VERSION 5.8 ;
BUSBITCHARS "[]" ;
DIVIDERCHAR "/" ;
UNITS
    DATABASE MICRONS 1000 ;
END UNITS

VIA PLL_ANALOG_MACRO_via2_3_960_480_1_3_320_320
  VIARULE M1M2_PR ;
  CUTSIZE 0.15 0.15 ;
  LAYERS met1 via met2 ;
  CUTSPACING 0.17 0.17 ;
  ENCLOSURE 0.085 0.165 0.055 0.085 ;
  ROWCOL 1 3 ;
END PLL_ANALOG_MACRO_via2_3_960_480_1_3_320_320

VIA PLL_ANALOG_MACRO_via3_4_960_480_1_2_400_400
  VIARULE M2M3_PR ;
  CUTSIZE 0.2 0.2 ;
  LAYERS met2 via2 met3 ;
  CUTSPACING 0.2 0.2 ;
  ENCLOSURE 0.04 0.085 0.065 0.065 ;
  ROWCOL 1 2 ;
END PLL_ANALOG_MACRO_via3_4_960_480_1_2_400_400

VIA PLL_ANALOG_MACRO_via4_5_960_480_1_2_400_400
  VIARULE M3M4_PR ;
  CUTSIZE 0.2 0.2 ;
  LAYERS met3 via3 met4 ;
  CUTSPACING 0.2 0.2 ;
  ENCLOSURE 0.09 0.06 0.18 0.065 ;
  ROWCOL 1 2 ;
END PLL_ANALOG_MACRO_via4_5_960_480_1_2_400_400

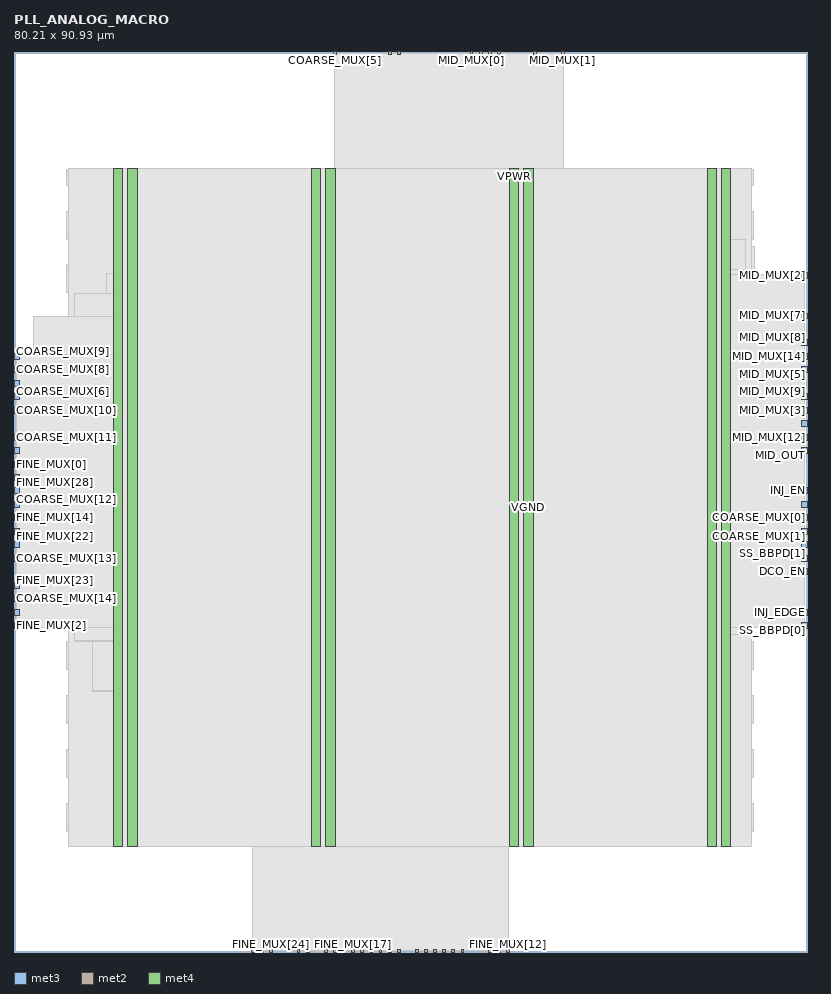
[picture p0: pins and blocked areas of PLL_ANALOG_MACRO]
MACRO PLL_ANALOG_MACRO
  FOREIGN PLL_ANALOG_MACRO 0 0 ;
  CLASS BLOCK ;
  SIZE 80.21 BY 90.93 ;
  PIN COARSE_MUX[0]
    DIRECTION INPUT ;
    USE SIGNAL ;
    PORT
      LAYER met3 ;
        RECT  79.61 43.56 80.21 44.16 ;
    END
  END COARSE_MUX[0]
  PIN COARSE_MUX[10]
    DIRECTION INPUT ;
    USE SIGNAL ;
    PORT
      LAYER met3 ;
        RECT  0 54.44 0.6 55.04 ;
    END
  END COARSE_MUX[10]
  PIN COARSE_MUX[11]
    DIRECTION INPUT ;
    USE SIGNAL ;
    PORT
      LAYER met3 ;
        RECT  0 51.72 0.6 52.32 ;
    END
  END COARSE_MUX[11]
  PIN COARSE_MUX[12]
    DIRECTION INPUT ;
    USE SIGNAL ;
    PORT
      LAYER met3 ;
        RECT  0 44.92 0.6 45.52 ;
    END
  END COARSE_MUX[12]
  PIN COARSE_MUX[13]
    DIRECTION INPUT ;
    USE SIGNAL ;
    PORT
      LAYER met3 ;
        RECT  0 39.48 0.6 40.08 ;
    END
  END COARSE_MUX[13]
  PIN COARSE_MUX[14]
    DIRECTION INPUT ;
    USE SIGNAL ;
    PORT
      LAYER met3 ;
        RECT  0 35.4 0.6 36 ;
    END
  END COARSE_MUX[14]
  PIN COARSE_MUX[1]
    DIRECTION INPUT ;
    USE SIGNAL ;
    PORT
      LAYER met3 ;
        RECT  79.61 42.2 80.21 42.8 ;
    END
  END COARSE_MUX[1]
  PIN COARSE_MUX[2]
    DIRECTION INPUT ;
    USE SIGNAL ;
    PORT
      LAYER met3 ;
        RECT  0 46.28 0.6 46.88 ;
    END
  END COARSE_MUX[2]
  PIN COARSE_MUX[3]
    DIRECTION INPUT ;
    USE SIGNAL ;
    PORT
      LAYER met2 ;
        RECT  37.81 90.65 38.09 90.93 ;
    END
  END COARSE_MUX[3]
  PIN COARSE_MUX[4]
    DIRECTION INPUT ;
    USE SIGNAL ;
    PORT
      LAYER met2 ;
        RECT  38.73 90.65 39.01 90.93 ;
    END
  END COARSE_MUX[4]
  PIN COARSE_MUX[5]
    DIRECTION INPUT ;
    USE SIGNAL ;
    PORT
      LAYER met2 ;
        RECT  32.29 90.65 32.57 90.93 ;
    END
  END COARSE_MUX[5]
  PIN COARSE_MUX[6]
    DIRECTION INPUT ;
    USE SIGNAL ;
    PORT
      LAYER met3 ;
        RECT  0 55.8 0.6 56.4 ;
    END
  END COARSE_MUX[6]
  PIN COARSE_MUX[7]
    DIRECTION INPUT ;
    USE SIGNAL ;
    PORT
      LAYER met3 ;
        RECT  0 57.16 0.6 57.76 ;
    END
  END COARSE_MUX[7]
  PIN COARSE_MUX[8]
    DIRECTION INPUT ;
    USE SIGNAL ;
    PORT
      LAYER met3 ;
        RECT  0 58.52 0.6 59.12 ;
    END
  END COARSE_MUX[8]
  PIN COARSE_MUX[9]
    DIRECTION INPUT ;
    USE SIGNAL ;
    PORT
      LAYER met3 ;
        RECT  0 59.88 0.6 60.48 ;
    END
  END COARSE_MUX[9]
  PIN DCO_EN
    DIRECTION INPUT ;
    USE SIGNAL ;
    PORT
      LAYER met3 ;
        RECT  79.61 38.12 80.21 38.72 ;
    END
  END DCO_EN
  PIN FINE_MUX[0]
    DIRECTION INPUT ;
    USE SIGNAL ;
    PORT
      LAYER met3 ;
        RECT  0 49 0.6 49.6 ;
    END
  END FINE_MUX[0]
  PIN FINE_MUX[10]
    DIRECTION INPUT ;
    USE SIGNAL ;
    PORT
      LAYER met2 ;
        RECT  43.33 0 43.61 0.28 ;
    END
  END FINE_MUX[10]
  PIN FINE_MUX[11]
    DIRECTION INPUT ;
    USE SIGNAL ;
    PORT
      LAYER met2 ;
        RECT  41.49 0 41.77 0.28 ;
    END
  END FINE_MUX[11]
  PIN FINE_MUX[12]
    DIRECTION INPUT ;
    USE SIGNAL ;
    PORT
      LAYER met2 ;
        RECT  49.77 0 50.05 0.28 ;
    END
  END FINE_MUX[12]
  PIN FINE_MUX[13]
    DIRECTION INPUT ;
    USE SIGNAL ;
    PORT
      LAYER met2 ;
        RECT  37.81 0 38.09 0.28 ;
    END
  END FINE_MUX[13]
  PIN FINE_MUX[14]
    DIRECTION INPUT ;
    USE SIGNAL ;
    PORT
      LAYER met3 ;
        RECT  0 43.56 0.6 44.16 ;
    END
  END FINE_MUX[14]
  PIN FINE_MUX[15]
    DIRECTION INPUT ;
    USE SIGNAL ;
    PORT
      LAYER met2 ;
        RECT  40.57 0 40.85 0.28 ;
    END
  END FINE_MUX[15]
  PIN FINE_MUX[16]
    DIRECTION INPUT ;
    USE SIGNAL ;
    PORT
      LAYER met2 ;
        RECT  35.05 0 35.33 0.28 ;
    END
  END FINE_MUX[16]
  PIN FINE_MUX[17]
    DIRECTION INPUT ;
    USE SIGNAL ;
    PORT
      LAYER met2 ;
        RECT  34.13 0 34.41 0.28 ;
    END
  END FINE_MUX[17]
  PIN FINE_MUX[18]
    DIRECTION INPUT ;
    USE SIGNAL ;
    PORT
      LAYER met2 ;
        RECT  32.29 0 32.57 0.28 ;
    END
  END FINE_MUX[18]
  PIN FINE_MUX[19]
    DIRECTION INPUT ;
    USE SIGNAL ;
    PORT
      LAYER met2 ;
        RECT  29.53 0 29.81 0.28 ;
    END
  END FINE_MUX[19]
  PIN FINE_MUX[1]
    DIRECTION INPUT ;
    USE SIGNAL ;
    PORT
      LAYER met2 ;
        RECT  48.85 0 49.13 0.28 ;
    END
  END FINE_MUX[1]
  PIN FINE_MUX[20]
    DIRECTION INPUT ;
    USE SIGNAL ;
    PORT
      LAYER met2 ;
        RECT  44.25 0 44.53 0.28 ;
    END
  END FINE_MUX[20]
  PIN FINE_MUX[21]
    DIRECTION INPUT ;
    USE SIGNAL ;
    PORT
      LAYER met2 ;
        RECT  42.41 0 42.69 0.28 ;
    END
  END FINE_MUX[21]
  PIN FINE_MUX[22]
    DIRECTION INPUT ;
    USE SIGNAL ;
    PORT
      LAYER met3 ;
        RECT  0 42.2 0.6 42.8 ;
    END
  END FINE_MUX[22]
  PIN FINE_MUX[23]
    DIRECTION INPUT ;
    USE SIGNAL ;
    PORT
      LAYER met3 ;
        RECT  0 36.76 0.6 37.36 ;
    END
  END FINE_MUX[23]
  PIN FINE_MUX[24]
    DIRECTION INPUT ;
    USE SIGNAL ;
    PORT
      LAYER met2 ;
        RECT  25.85 0 26.13 0.28 ;
    END
  END FINE_MUX[24]
  PIN FINE_MUX[25]
    DIRECTION INPUT ;
    USE SIGNAL ;
    PORT
      LAYER met2 ;
        RECT  24.93 0 25.21 0.28 ;
    END
  END FINE_MUX[25]
  PIN FINE_MUX[26]
    DIRECTION INPUT ;
    USE SIGNAL ;
    PORT
      LAYER met3 ;
        RECT  0 40.84 0.6 41.44 ;
    END
  END FINE_MUX[26]
  PIN FINE_MUX[27]
    DIRECTION INPUT ;
    USE SIGNAL ;
    PORT
      LAYER met2 ;
        RECT  31.37 0 31.65 0.28 ;
    END
  END FINE_MUX[27]
  PIN FINE_MUX[28]
    DIRECTION INPUT ;
    USE SIGNAL ;
    PORT
      LAYER met3 ;
        RECT  0 47.64 0.6 48.24 ;
    END
  END FINE_MUX[28]
  PIN FINE_MUX[29]
    DIRECTION INPUT ;
    USE SIGNAL ;
    PORT
      LAYER met2 ;
        RECT  47.93 0 48.21 0.28 ;
    END
  END FINE_MUX[29]
  PIN FINE_MUX[2]
    DIRECTION INPUT ;
    USE SIGNAL ;
    PORT
      LAYER met3 ;
        RECT  0 32.68 0.6 33.28 ;
    END
  END FINE_MUX[2]
  PIN FINE_MUX[30]
    DIRECTION INPUT ;
    USE SIGNAL ;
    PORT
      LAYER met2 ;
        RECT  35.97 0 36.25 0.28 ;
    END
  END FINE_MUX[30]
  PIN FINE_MUX[3]
    DIRECTION INPUT ;
    USE SIGNAL ;
    PORT
      LAYER met3 ;
        RECT  0 50.36 0.6 50.96 ;
    END
  END FINE_MUX[3]
  PIN FINE_MUX[4]
    DIRECTION INPUT ;
    USE SIGNAL ;
    PORT
      LAYER met2 ;
        RECT  36.89 0 37.17 0.28 ;
    END
  END FINE_MUX[4]
  PIN FINE_MUX[5]
    DIRECTION INPUT ;
    USE SIGNAL ;
    PORT
      LAYER met3 ;
        RECT  0 34.04 0.6 34.64 ;
    END
  END FINE_MUX[5]
  PIN FINE_MUX[6]
    DIRECTION INPUT ;
    USE SIGNAL ;
    PORT
      LAYER met2 ;
        RECT  45.17 0 45.45 0.28 ;
    END
  END FINE_MUX[6]
  PIN FINE_MUX[7]
    DIRECTION INPUT ;
    USE SIGNAL ;
    PORT
      LAYER met2 ;
        RECT  38.73 0 39.01 0.28 ;
    END
  END FINE_MUX[7]
  PIN FINE_MUX[8]
    DIRECTION INPUT ;
    USE SIGNAL ;
    PORT
      LAYER met2 ;
        RECT  24.01 0 24.29 0.28 ;
    END
  END FINE_MUX[8]
  PIN FINE_MUX[9]
    DIRECTION INPUT ;
    USE SIGNAL ;
    PORT
      LAYER met2 ;
        RECT  28.61 0 28.89 0.28 ;
    END
  END FINE_MUX[9]
  PIN INJ_EDGE
    DIRECTION OUTPUT ;
    USE SIGNAL ;
    PORT
      LAYER met3 ;
        RECT  79.61 34.04 80.21 34.64 ;
    END
  END INJ_EDGE
  PIN INJ_EN
    DIRECTION INPUT ;
    USE SIGNAL ;
    PORT
      LAYER met3 ;
        RECT  79.61 46.28 80.21 46.88 ;
    END
  END INJ_EN
  PIN MID_MUX[0]
    DIRECTION INPUT ;
    USE SIGNAL ;
    PORT
      LAYER met2 ;
        RECT  46.09 90.65 46.37 90.93 ;
    END
  END MID_MUX[0]
  PIN MID_MUX[10]
    DIRECTION INPUT ;
    USE SIGNAL ;
    PORT
      LAYER met2 ;
        RECT  47.01 90.65 47.29 90.93 ;
    END
  END MID_MUX[10]
  PIN MID_MUX[11]
    DIRECTION INPUT ;
    USE SIGNAL ;
    PORT
      LAYER met2 ;
        RECT  52.53 90.65 52.81 90.93 ;
    END
  END MID_MUX[11]
  PIN MID_MUX[12]
    DIRECTION INPUT ;
    USE SIGNAL ;
    PORT
      LAYER met3 ;
        RECT  79.61 51.72 80.21 52.32 ;
    END
  END MID_MUX[12]
  PIN MID_MUX[13]
    DIRECTION INPUT ;
    USE SIGNAL ;
    PORT
      LAYER met2 ;
        RECT  48.85 90.65 49.13 90.93 ;
    END
  END MID_MUX[13]
  PIN MID_MUX[14]
    DIRECTION INPUT ;
    USE SIGNAL ;
    PORT
      LAYER met3 ;
        RECT  79.61 59.88 80.21 60.48 ;
    END
  END MID_MUX[14]
  PIN MID_MUX[1]
    DIRECTION INPUT ;
    USE SIGNAL ;
    PORT
      LAYER met2 ;
        RECT  55.29 90.65 55.57 90.93 ;
    END
  END MID_MUX[1]
  PIN MID_MUX[2]
    DIRECTION INPUT ;
    USE SIGNAL ;
    PORT
      LAYER met3 ;
        RECT  79.61 68.04 80.21 68.64 ;
    END
  END MID_MUX[2]
  PIN MID_MUX[3]
    DIRECTION INPUT ;
    USE SIGNAL ;
    PORT
      LAYER met3 ;
        RECT  79.61 54.44 80.21 55.04 ;
    END
  END MID_MUX[3]
  PIN MID_MUX[4]
    DIRECTION INPUT ;
    USE SIGNAL ;
    PORT
      LAYER met2 ;
        RECT  47.93 90.65 48.21 90.93 ;
    END
  END MID_MUX[4]
  PIN MID_MUX[5]
    DIRECTION INPUT ;
    USE SIGNAL ;
    PORT
      LAYER met3 ;
        RECT  79.61 58.52 80.21 59.12 ;
    END
  END MID_MUX[5]
  PIN MID_MUX[6]
    DIRECTION INPUT ;
    USE SIGNAL ;
    PORT
      LAYER met3 ;
        RECT  79.61 53.08 80.21 53.68 ;
    END
  END MID_MUX[6]
  PIN MID_MUX[7]
    DIRECTION INPUT ;
    USE SIGNAL ;
    PORT
      LAYER met3 ;
        RECT  79.61 63.96 80.21 64.56 ;
    END
  END MID_MUX[7]
  PIN MID_MUX[8]
    DIRECTION INPUT ;
    USE SIGNAL ;
    PORT
      LAYER met3 ;
        RECT  79.61 61.24 80.21 61.84 ;
    END
  END MID_MUX[8]
  PIN MID_MUX[9]
    DIRECTION INPUT ;
    USE SIGNAL ;
    PORT
      LAYER met3 ;
        RECT  79.61 55.8 80.21 56.4 ;
    END
  END MID_MUX[9]
  PIN MID_OUT
    DIRECTION OUTPUT ;
    USE SIGNAL ;
    PORT
      LAYER met3 ;
        RECT  79.61 50.36 80.21 50.96 ;
    END
  END MID_OUT
  PIN OUT
    DIRECTION OUTPUT ;
    USE SIGNAL ;
    PORT
      LAYER met3 ;
        RECT  79.61 40.84 80.21 41.44 ;
    END
  END OUT
  PIN REF
    DIRECTION INPUT ;
    USE SIGNAL ;
    PORT
      LAYER met3 ;
        RECT  79.61 44.92 80.21 45.52 ;
    END
  END REF
  PIN SS_BBPD[0]
    DIRECTION OUTPUT ;
    USE SIGNAL ;
    PORT
      LAYER met3 ;
        RECT  79.61 32.68 80.21 33.28 ;
    END
  END SS_BBPD[0]
  PIN SS_BBPD[1]
    DIRECTION OUTPUT ;
    USE SIGNAL ;
    PORT
      LAYER met3 ;
        RECT  79.61 39.48 80.21 40.08 ;
    END
  END SS_BBPD[1]
  PIN VGND
    DIRECTION INOUT ;
    USE GROUND ;
    PORT
      LAYER met4 ;
        RECT  71.48 10.64 72.44 79.12 ;
        RECT  51.48 10.64 52.44 79.12 ;
        RECT  31.48 10.64 32.44 79.12 ;
        RECT  11.48 10.64 12.44 79.12 ;
    END
  END VGND
  PIN VPWR
    DIRECTION INOUT ;
    USE POWER ;
    PORT
      LAYER met4 ;
        RECT  70.04 10.64 71 79.12 ;
        RECT  50.04 10.64 51 79.12 ;
        RECT  30.04 10.64 31 79.12 ;
        RECT  10.04 10.64 11 79.12 ;
    END
  END VPWR
  OBS
    LAYER nwell ;
     RECT  5.33 12.19 74.71 15.01 ;
     RECT  5.33 17.63 74.71 20.45 ;
     RECT  5.33 23.07 74.71 25.89 ;
     RECT  5.33 28.51 74.71 31.33 ;
     RECT  5.33 33.95 74.71 36.77 ;
     RECT  5.33 39.39 74.71 42.21 ;
     RECT  5.33 44.83 74.71 47.65 ;
     RECT  5.33 50.27 74.71 53.09 ;
     RECT  5.33 55.71 74.71 58.53 ;
     RECT  5.33 61.15 74.71 63.97 ;
     RECT  5.33 66.59 74.71 69.41 ;
     RECT  5.33 72.03 74.71 74.85 ;
     RECT  5.33 77.47 74.71 79.07 ;
    LAYER pwell ;
     RECT  18.53 10.78 18.73 10.805 ;
     RECT  56.25 10.78 56.45 10.805 ;
     RECT  72.79 10.77 73.04 10.805 ;
     RECT  6.1 10.77 6.5 10.86 ;
     RECT  53.95 10.78 54.27 10.86 ;
     RECT  57.62 10.77 58.02 10.86 ;
     RECT  65.44 10.77 65.84 10.86 ;
     RECT  72.79 10.805 73.06 10.86 ;
     RECT  5.61 10.76 5.92 10.99 ;
     RECT  5.98 10.86 13.34 10.99 ;
     RECT  18.48 10.805 18.73 10.99 ;
     RECT  21.17 10.78 21.51 10.99 ;
     RECT  23.01 10.78 23.35 10.99 ;
     RECT  24.85 10.78 25.19 10.99 ;
     RECT  25.39 10.76 25.7 10.99 ;
     RECT  28.07 10.78 28.41 10.99 ;
     RECT  29.91 10.78 30.25 10.99 ;
     RECT  31.75 10.78 32.09 10.99 ;
     RECT  33.59 10.78 33.93 10.99 ;
     RECT  35.43 10.78 35.77 10.99 ;
     RECT  37.27 10.78 37.61 10.99 ;
     RECT  39.11 10.78 39.45 10.99 ;
     RECT  40.95 10.78 41.29 10.99 ;
     RECT  42.79 10.78 43.13 10.99 ;
     RECT  43.35 10.78 43.69 10.99 ;
     RECT  45.17 10.76 45.48 10.99 ;
     RECT  45.65 10.78 45.99 10.99 ;
     RECT  48.41 10.78 48.75 10.99 ;
     RECT  50.25 10.78 50.59 10.99 ;
     RECT  52.09 10.78 52.43 10.99 ;
     RECT  56.25 10.805 56.5 10.99 ;
     RECT  57.5 10.86 64.86 10.99 ;
     RECT  64.95 10.76 65.26 10.99 ;
     RECT  65.32 10.86 74.06 10.99 ;
     RECT  74.12 10.76 74.43 10.99 ;
     RECT  21.07 10.99 21.51 11.03 ;
     RECT  22.91 10.99 23.35 11.03 ;
     RECT  24.75 10.99 25.19 11.03 ;
     RECT  27.97 10.99 28.41 11.03 ;
     RECT  29.81 10.99 30.25 11.03 ;
     RECT  31.65 10.99 32.09 11.03 ;
     RECT  33.49 10.99 33.93 11.03 ;
     RECT  35.33 10.99 35.77 11.03 ;
     RECT  37.17 10.99 37.61 11.03 ;
     RECT  39.01 10.99 39.45 11.03 ;
     RECT  40.85 10.99 41.29 11.03 ;
     RECT  42.69 10.99 43.13 11.03 ;
     RECT  43.35 10.99 43.79 11.03 ;
     RECT  45.65 10.99 46.09 11.03 ;
     RECT  48.41 10.99 48.85 11.03 ;
     RECT  50.25 10.99 50.69 11.03 ;
     RECT  52.09 10.99 52.53 11.03 ;
     RECT  21.17 11.03 21.51 11.09 ;
     RECT  23.01 11.03 23.35 11.09 ;
     RECT  24.85 11.03 25.19 11.09 ;
     RECT  28.07 11.03 28.41 11.09 ;
     RECT  29.91 11.03 30.25 11.09 ;
     RECT  31.75 11.03 32.09 11.09 ;
     RECT  33.59 11.03 33.93 11.09 ;
     RECT  35.43 11.03 35.77 11.09 ;
     RECT  37.27 11.03 37.61 11.09 ;
     RECT  39.11 11.03 39.45 11.09 ;
     RECT  40.95 11.03 41.29 11.09 ;
     RECT  42.79 11.03 43.13 11.09 ;
     RECT  43.35 11.03 43.69 11.09 ;
     RECT  45.65 11.03 45.99 11.09 ;
     RECT  48.41 11.03 48.75 11.09 ;
     RECT  50.25 11.03 50.59 11.09 ;
     RECT  52.09 11.03 52.43 11.09 ;
     RECT  5.52 10.99 13.34 11.9 ;
     RECT  17.48 10.99 18.86 11.9 ;
     RECT  19.81 11.09 21.59 11.9 ;
     RECT  21.65 11.09 23.43 11.9 ;
     RECT  23.49 11.09 25.27 11.9 ;
     RECT  25.3 10.99 25.76 11.9 ;
     RECT  26.71 11.09 28.49 11.9 ;
     RECT  28.55 11.09 30.33 11.9 ;
     RECT  30.39 11.09 32.17 11.9 ;
     RECT  32.23 11.09 34.01 11.9 ;
     RECT  34.07 11.09 35.85 11.9 ;
     RECT  35.91 11.09 37.69 11.9 ;
     RECT  37.75 11.09 39.53 11.9 ;
     RECT  39.59 11.09 41.37 11.9 ;
     RECT  41.43 11.09 43.21 11.9 ;
     RECT  43.27 11.09 45.05 11.9 ;
     RECT  45.08 10.99 45.54 11.9 ;
     RECT  45.57 11.09 47.35 11.9 ;
     RECT  48.33 11.09 50.11 11.9 ;
     RECT  50.17 11.09 51.95 11.9 ;
     RECT  52.01 11.09 53.79 11.9 ;
     RECT  53.82 10.86 55.66 11.9 ;
     RECT  56.12 10.99 74.52 11.9 ;
     RECT  32.23 15.3 34.01 16.11 ;
     RECT  33.59 16.11 33.93 16.17 ;
     RECT  5.52 15.3 15.18 16.21 ;
     RECT  33.49 16.17 33.93 16.21 ;
     RECT  34.04 15.3 45.54 16.21 ;
     RECT  46.46 15.3 73.6 16.21 ;
     RECT  74.06 15.3 74.52 16.21 ;
     RECT  16.1 15.3 19.78 16.22 ;
     RECT  20.24 15.3 23.92 16.22 ;
     RECT  24.84 15.3 32.2 16.22 ;
     RECT  34.04 16.21 45.08 16.22 ;
     RECT  46.46 16.21 50.14 16.22 ;
     RECT  51.52 16.21 73.6 16.22 ;
     RECT  20.83 16.22 21.03 16.245 ;
     RECT  22.21 16.22 22.41 16.245 ;
     RECT  26.81 16.22 27.01 16.245 ;
     RECT  35.09 16.22 35.29 16.245 ;
     RECT  41.07 16.22 41.27 16.245 ;
     RECT  43.37 16.22 43.57 16.245 ;
     RECT  47.51 16.22 47.71 16.245 ;
     RECT  52.57 16.22 52.77 16.245 ;
     RECT  5.98 16.21 15.18 16.3 ;
     RECT  17.1 16.22 17.35 16.3 ;
     RECT  19.33 16.22 19.65 16.3 ;
     RECT  20.37 16.22 20.69 16.3 ;
     RECT  44.75 16.22 45.07 16.3 ;
     RECT  45.17 16.21 45.48 16.3 ;
     RECT  53.94 16.22 54.34 16.3 ;
     RECT  55.33 16.22 55.65 16.3 ;
     RECT  57.63 16.22 57.88 16.3 ;
     RECT  58.88 16.22 73.6 16.3 ;
     RECT  53.82 16.3 74.06 16.34 ;
     RECT  22.67 16.22 22.92 16.395 ;
     RECT  27.27 16.22 27.52 16.395 ;
     RECT  30.95 16.22 31.2 16.395 ;
     RECT  40.15 16.22 40.4 16.395 ;
     RECT  43.83 16.22 44.08 16.395 ;
     RECT  48.89 16.22 49.14 16.395 ;
     RECT  50.27 16.21 50.52 16.395 ;
     RECT  22.67 16.395 22.87 16.42 ;
     RECT  24.85 16.22 25.29 16.42 ;
     RECT  27.27 16.395 27.47 16.42 ;
     RECT  28.65 16.22 28.97 16.42 ;
     RECT  30.95 16.395 31.15 16.42 ;
     RECT  32.79 16.22 33.11 16.42 ;
     RECT  33.59 16.21 33.93 16.42 ;
     RECT  34.17 16.22 34.49 16.42 ;
     RECT  35.09 16.245 35.34 16.42 ;
     RECT  37.85 16.22 38.17 16.42 ;
     RECT  40.15 16.395 40.35 16.42 ;
     RECT  41.53 16.22 41.85 16.42 ;
     RECT  43.83 16.395 44.03 16.42 ;
     RECT  46.59 16.22 46.91 16.42 ;
     RECT  48.89 16.395 49.09 16.42 ;
     RECT  50.27 16.395 50.47 16.42 ;
     RECT  51.65 16.22 51.97 16.42 ;
     RECT  5.61 16.21 5.92 16.43 ;
     RECT  5.98 16.3 20.7 16.43 ;
     RECT  20.83 16.245 21.08 16.43 ;
     RECT  22.21 16.245 22.46 16.43 ;
     RECT  24.85 16.42 25.19 16.43 ;
     RECT  25.39 16.22 25.7 16.43 ;
     RECT  26.81 16.245 27.06 16.43 ;
     RECT  28.65 16.42 28.9 16.43 ;
     RECT  30.01 16.22 30.35 16.43 ;
     RECT  36.45 16.22 36.79 16.43 ;
     RECT  38.29 16.22 38.63 16.43 ;
     RECT  41.07 16.245 41.32 16.43 ;
     RECT  43.37 16.245 43.62 16.43 ;
     RECT  44.62 16.3 46.46 16.43 ;
     RECT  47.51 16.245 47.76 16.43 ;
     RECT  52.57 16.245 52.82 16.43 ;
     RECT  53.82 16.34 61.18 16.43 ;
     RECT  64.95 16.34 65.26 16.43 ;
     RECT  65.32 16.34 74.06 16.43 ;
     RECT  74.12 16.21 74.43 16.43 ;
     RECT  24.75 16.43 25.19 16.47 ;
     RECT  30.01 16.43 30.45 16.47 ;
     RECT  36.45 16.43 36.89 16.47 ;
     RECT  38.29 16.43 38.73 16.47 ;
     RECT  24.85 16.47 25.19 16.53 ;
     RECT  30.01 16.47 30.35 16.53 ;
     RECT  36.45 16.47 36.79 16.53 ;
     RECT  38.29 16.47 38.63 16.53 ;
     RECT  5.52 16.43 23.46 17.34 ;
     RECT  23.49 16.53 25.27 17.34 ;
     RECT  25.3 16.43 25.76 17.34 ;
     RECT  26.68 16.43 28.06 17.34 ;
     RECT  28.52 16.43 29.9 17.34 ;
     RECT  29.93 16.53 31.71 17.34 ;
     RECT  32.66 16.42 36.34 17.34 ;
     RECT  36.37 16.53 38.15 17.34 ;
     RECT  38.21 16.53 39.99 17.34 ;
     RECT  40.94 16.43 42.32 17.34 ;
     RECT  43.24 16.43 46.46 17.34 ;
     RECT  47.38 16.43 48.76 17.34 ;
     RECT  52.44 16.43 61.18 17.34 ;
     RECT  64.86 16.43 74.52 17.34 ;
     RECT  5.52 20.74 27.6 21.65 ;
     RECT  28.52 20.74 29.9 21.65 ;
     RECT  33.58 20.74 34.96 21.65 ;
     RECT  35.42 20.74 36.8 21.65 ;
     RECT  37.26 20.74 38.64 21.65 ;
     RECT  39.56 20.74 40.94 21.65 ;
     RECT  45.08 20.74 45.54 21.65 ;
     RECT  50.6 20.74 70.38 21.65 ;
     RECT  74.06 20.74 74.52 21.65 ;
     RECT  5.98 21.65 27.6 21.66 ;
     RECT  46.46 20.74 50.14 21.66 ;
     RECT  51.98 21.65 70.38 21.66 ;
     RECT  31.87 21.66 32.07 21.685 ;
     RECT  33.25 21.66 33.45 21.685 ;
     RECT  41.07 21.66 41.27 21.685 ;
     RECT  42.91 21.66 43.11 21.685 ;
     RECT  72.79 21.65 73.04 21.685 ;
     RECT  44.29 21.66 44.61 21.74 ;
     RECT  45.17 21.65 45.48 21.74 ;
     RECT  47.96 21.66 48.36 21.74 ;
     RECT  48.89 21.66 49.14 21.74 ;
     RECT  51.6 21.65 51.85 21.74 ;
     RECT  52.11 21.66 52.43 21.74 ;
     RECT  54.41 21.66 54.66 21.74 ;
     RECT  55.32 21.66 70.38 21.74 ;
     RECT  72.79 21.685 73.06 21.74 ;
     RECT  5.98 21.66 22.08 21.78 ;
     RECT  25.76 21.66 27.6 21.78 ;
     RECT  47.84 21.74 74.06 21.78 ;
     RECT  20.81 21.78 21.08 21.835 ;
     RECT  24.51 21.66 24.76 21.835 ;
     RECT  28.65 21.65 28.9 21.835 ;
     RECT  33.71 21.65 33.96 21.835 ;
     RECT  35.55 21.65 35.8 21.835 ;
     RECT  39.69 21.65 39.94 21.835 ;
     RECT  22.21 21.66 22.53 21.86 ;
     RECT  24.51 21.835 24.71 21.86 ;
     RECT  25.89 21.78 26.21 21.86 ;
     RECT  26.76 21.78 27.01 21.86 ;
     RECT  28.65 21.835 28.85 21.86 ;
     RECT  28.99 21.66 29.31 21.86 ;
     RECT  29.57 21.66 29.89 21.86 ;
     RECT  31.87 21.685 32.12 21.86 ;
     RECT  33.71 21.835 33.91 21.86 ;
     RECT  35.09 21.66 35.41 21.86 ;
     RECT  35.55 21.835 35.75 21.86 ;
     RECT  37.39 21.65 37.64 21.86 ;
     RECT  38.77 21.66 39.09 21.86 ;
     RECT  39.69 21.835 39.89 21.86 ;
     RECT  41.07 21.685 41.32 21.86 ;
     RECT  46.59 21.66 46.91 21.86 ;
     RECT  5.61 21.65 5.92 21.87 ;
     RECT  5.98 21.78 20.7 21.87 ;
     RECT  20.81 21.835 21.06 21.87 ;
     RECT  25.39 21.66 25.7 21.87 ;
     RECT  25.76 21.86 33.12 21.87 ;
     RECT  33.25 21.685 33.5 21.87 ;
     RECT  42.91 21.685 43.16 21.87 ;
     RECT  44.16 21.74 46 21.87 ;
     RECT  46.59 21.86 46.84 21.87 ;
     RECT  47.84 21.78 64.4 21.87 ;
     RECT  64.95 21.78 65.26 21.87 ;
     RECT  65.32 21.78 74.06 21.87 ;
     RECT  74.12 21.65 74.43 21.87 ;
     RECT  5.52 21.87 20.7 22.78 ;
     RECT  25.3 21.87 34.5 22.78 ;
     RECT  34.96 21.86 42.32 22.78 ;
     RECT  42.78 21.87 46 22.78 ;
     RECT  46.46 21.87 64.4 22.78 ;
     RECT  64.86 21.87 74.52 22.78 ;
     RECT  5.52 26.18 33.12 27.09 ;
     RECT  33.58 26.18 40.48 27.09 ;
     RECT  41.4 26.18 73.14 27.09 ;
     RECT  74.06 26.18 74.52 27.09 ;
     RECT  33.24 27.09 37.26 27.1 ;
     RECT  41.4 27.09 45.08 27.1 ;
     RECT  45.54 27.09 73.14 27.1 ;
     RECT  7.95 27.1 8.15 27.125 ;
     RECT  9.2 27.09 33.12 27.18 ;
     RECT  33.24 27.1 33.64 27.18 ;
     RECT  34.58 27.1 34.83 27.18 ;
     RECT  36.81 27.1 37.13 27.18 ;
     RECT  37.39 27.09 37.64 27.18 ;
     RECT  38.64 27.09 40.48 27.18 ;
     RECT  40.6 27.09 41 27.18 ;
     RECT  41.53 27.1 41.85 27.18 ;
     RECT  43.83 27.1 44.08 27.18 ;
     RECT  45.17 27.09 45.48 27.18 ;
     RECT  45.67 27.1 45.99 27.18 ;
     RECT  47.96 27.1 48.36 27.18 ;
     RECT  49.22 27.1 73.14 27.18 ;
     RECT  5.98 27.09 7.82 27.22 ;
     RECT  9.2 27.18 73.14 27.22 ;
     RECT  8.82 27.09 9.07 27.275 ;
     RECT  6.11 27.22 6.43 27.3 ;
     RECT  7.9 27.125 8.15 27.3 ;
     RECT  8.87 27.275 9.07 27.3 ;
     RECT  9.32 27.22 9.72 27.3 ;
     RECT  10.13 27.22 10.45 27.3 ;
     RECT  10.58 27.22 25.3 27.3 ;
     RECT  71.43 27.22 71.75 27.3 ;
     RECT  5.61 27.09 5.92 27.31 ;
     RECT  6.9 27.3 25.3 27.31 ;
     RECT  25.39 27.22 25.7 27.31 ;
     RECT  25.76 27.22 55.2 27.31 ;
     RECT  56.7 27.22 57.1 27.31 ;
     RECT  60.37 27.22 60.71 27.31 ;
     RECT  62.67 27.22 63.01 27.31 ;
     RECT  64.06 27.22 64.46 27.31 ;
     RECT  64.95 27.22 65.26 27.31 ;
     RECT  74.12 27.09 74.43 27.31 ;
     RECT  60.37 27.31 60.81 27.35 ;
     RECT  62.67 27.31 63.11 27.35 ;
     RECT  60.37 27.35 60.71 27.41 ;
     RECT  62.67 27.35 63.01 27.41 ;
     RECT  65.43 27.22 65.73 27.42 ;
     RECT  65.43 27.42 73.36 27.44 ;
     RECT  5.52 27.31 5.98 28.22 ;
     RECT  6.9 27.31 55.2 28.22 ;
     RECT  58.88 27.22 60.26 28.22 ;
     RECT  60.29 27.41 62.07 28.22 ;
     RECT  62.59 27.41 64.37 28.22 ;
     RECT  64.86 27.31 65.32 28.22 ;
     RECT  65.41 27.44 74.03 28.22 ;
     RECT  74.06 27.31 74.52 28.22 ;
     RECT  6.01 31.62 7.79 32.43 ;
     RECT  7.85 31.62 9.63 32.43 ;
     RECT  70.41 31.62 72.19 32.43 ;
     RECT  72.25 31.62 74.03 32.43 ;
     RECT  6.09 32.43 6.43 32.49 ;
     RECT  7.93 32.43 8.27 32.49 ;
     RECT  71.77 32.43 72.11 32.49 ;
     RECT  72.33 32.43 72.67 32.49 ;
     RECT  5.52 31.62 5.98 32.53 ;
     RECT  6.09 32.49 6.53 32.53 ;
     RECT  7.93 32.49 8.37 32.53 ;
     RECT  9.66 31.62 54.74 32.53 ;
     RECT  55.66 31.62 70.38 32.53 ;
     RECT  71.67 32.49 72.11 32.53 ;
     RECT  72.33 32.49 72.77 32.53 ;
     RECT  74.06 31.62 74.52 32.53 ;
     RECT  20.7 32.53 40.48 32.54 ;
     RECT  7.93 32.53 8.27 32.565 ;
     RECT  20.7 32.54 36.8 32.62 ;
     RECT  37.8 32.54 38.05 32.62 ;
     RECT  40.03 32.54 40.35 32.62 ;
     RECT  40.6 32.53 41 32.62 ;
     RECT  41.86 32.53 45.08 32.62 ;
     RECT  45.17 32.53 45.48 32.62 ;
     RECT  45.54 32.53 54.74 32.62 ;
     RECT  59.01 32.54 59.33 32.62 ;
     RECT  60.39 32.53 60.64 32.62 ;
     RECT  11.04 32.53 18.4 32.66 ;
     RECT  20.7 32.62 55.2 32.66 ;
     RECT  61.64 32.53 70.38 32.66 ;
     RECT  9.79 32.53 10.04 32.715 ;
     RECT  69.11 32.66 69.38 32.715 ;
     RECT  6.09 32.53 6.43 32.74 ;
     RECT  7.9 32.565 8.27 32.74 ;
     RECT  9.79 32.715 9.99 32.74 ;
     RECT  10.13 32.54 10.45 32.74 ;
     RECT  18.53 32.53 18.85 32.74 ;
     RECT  55.79 32.53 56.11 32.74 ;
     RECT  58.09 32.53 58.41 32.74 ;
     RECT  72.33 32.53 72.67 32.74 ;
     RECT  5.61 32.53 5.92 32.75 ;
     RECT  10.69 32.54 11.03 32.75 ;
     RECT  11.16 32.66 11.56 32.75 ;
     RECT  16.1 32.66 17.94 32.75 ;
     RECT  18.07 32.66 18.32 32.75 ;
     RECT  19.45 32.54 19.77 32.75 ;
     RECT  20.82 32.66 21.22 32.75 ;
     RECT  21.73 32.66 22.07 32.75 ;
     RECT  23.46 32.66 25.3 32.75 ;
     RECT  25.39 32.66 25.7 32.75 ;
     RECT  25.76 32.66 55.2 32.75 ;
     RECT  61.29 32.54 61.63 32.75 ;
     RECT  61.76 32.66 62.16 32.75 ;
     RECT  63.13 32.66 63.47 32.75 ;
     RECT  64.95 32.66 65.26 32.75 ;
     RECT  65.32 32.66 68.54 32.75 ;
     RECT  69.11 32.715 69.36 32.75 ;
     RECT  69.93 32.66 70.27 32.75 ;
     RECT  71.77 32.53 72.11 32.75 ;
     RECT  73.61 32.54 73.95 32.75 ;
     RECT  74.12 32.53 74.43 32.75 ;
     RECT  10.69 32.75 11.13 32.79 ;
     RECT  21.73 32.75 22.17 32.79 ;
     RECT  61.29 32.75 61.73 32.79 ;
     RECT  63.13 32.75 63.57 32.79 ;
     RECT  69.83 32.75 70.27 32.79 ;
     RECT  71.67 32.75 72.11 32.79 ;
     RECT  73.51 32.75 73.95 32.79 ;
     RECT  10.69 32.79 11.03 32.85 ;
     RECT  21.73 32.79 22.07 32.85 ;
     RECT  61.29 32.79 61.63 32.85 ;
     RECT  63.13 32.79 63.47 32.85 ;
     RECT  69.93 32.79 70.27 32.85 ;
     RECT  71.77 32.79 72.11 32.85 ;
     RECT  73.61 32.79 73.95 32.85 ;
     RECT  5.52 32.75 5.98 33.66 ;
     RECT  6.9 32.74 10.58 33.66 ;
     RECT  10.61 32.85 12.39 33.66 ;
     RECT  16.1 32.75 21.62 33.66 ;
     RECT  21.65 32.85 23.43 33.66 ;
     RECT  23.46 32.75 55.2 33.66 ;
     RECT  58.88 32.62 60.72 33.66 ;
     RECT  61.21 32.85 62.99 33.66 ;
     RECT  63.05 32.85 64.83 33.66 ;
     RECT  64.86 32.75 68.54 33.66 ;
     RECT  68.57 32.85 70.35 33.66 ;
     RECT  70.41 32.85 72.19 33.66 ;
     RECT  72.25 32.85 74.03 33.66 ;
     RECT  74.06 32.75 74.52 33.66 ;
     RECT  65.41 37.06 74.03 37.84 ;
     RECT  65.43 37.84 73.36 37.86 ;
     RECT  6.01 37.06 7.79 37.87 ;
     RECT  7.85 37.06 9.63 37.87 ;
     RECT  6.09 37.87 6.43 37.93 ;
     RECT  7.93 37.87 8.27 37.93 ;
     RECT  49.22 37.06 56.58 37.95 ;
     RECT  51.52 37.95 56.58 37.96 ;
     RECT  5.52 37.06 5.98 37.97 ;
     RECT  6.09 37.93 6.53 37.97 ;
     RECT  7.93 37.93 8.37 37.97 ;
     RECT  9.66 37.06 14.72 37.97 ;
     RECT  18.4 37.06 44.62 37.97 ;
     RECT  45.08 37.06 45.54 37.97 ;
     RECT  51.05 37.96 51.2 37.97 ;
     RECT  51.5 37.96 56.58 37.97 ;
     RECT  57.5 37.06 58.88 37.97 ;
     RECT  59.34 37.06 61.64 37.97 ;
     RECT  74.06 37.06 74.52 37.97 ;
     RECT  10.66 37.97 10.91 37.98 ;
     RECT  11.04 37.97 14.72 37.98 ;
     RECT  9.33 37.98 9.53 38.005 ;
     RECT  12.55 37.98 12.75 38.005 ;
     RECT  17.59 37.97 17.84 38.005 ;
     RECT  57.15 37.97 57.4 38.005 ;
     RECT  58.5 37.97 58.75 38.005 ;
     RECT  66.37 37.98 66.57 38.005 ;
     RECT  69.11 37.97 69.36 38.005 ;
     RECT  17.59 38.005 17.86 38.06 ;
     RECT  18.4 37.97 20.24 38.06 ;
     RECT  22.54 37.97 44.62 38.06 ;
     RECT  45.17 37.97 45.48 38.06 ;
     RECT  47.96 37.97 48.36 38.06 ;
     RECT  49.22 37.95 50.6 38.06 ;
     RECT  53.44 37.97 53.69 38.06 ;
     RECT  53.95 37.97 54.2 38.06 ;
     RECT  55.33 37.98 55.65 38.06 ;
     RECT  56.2 37.97 56.45 38.06 ;
     RECT  57.15 38.005 57.42 38.06 ;
     RECT  62.23 37.98 62.55 38.06 ;
     RECT  69.11 38.005 69.38 38.06 ;
     RECT  17.48 38.06 20.24 38.1 ;
     RECT  22.54 38.06 58.42 38.1 ;
     RECT  10.66 37.98 11.03 38.155 ;
     RECT  13.47 37.98 13.72 38.155 ;
     RECT  58.5 38.005 58.8 38.155 ;
     RECT  65.43 37.86 65.73 38.155 ;
     RECT  6.09 37.97 6.43 38.18 ;
     RECT  7.03 37.98 7.35 38.18 ;
     RECT  7.93 37.97 8.27 38.18 ;
     RECT  9.33 38.005 9.58 38.18 ;
     RECT  11.17 37.98 11.49 38.18 ;
     RECT  13.47 38.155 13.67 38.18 ;
     RECT  20.37 37.97 20.69 38.18 ;
     RECT  61.19 37.97 61.51 38.18 ;
     RECT  65.43 38.155 65.64 38.18 ;
     RECT  66.32 38.005 66.57 38.18 ;
     RECT  68.55 37.98 68.87 38.18 ;
     RECT  69 38.06 70.38 38.18 ;
     RECT  5.61 37.97 5.92 38.19 ;
     RECT  10.69 38.155 11.03 38.19 ;
     RECT  12.55 38.005 12.8 38.19 ;
     RECT  17.48 38.1 18.86 38.19 ;
     RECT  18.99 38.1 19.31 38.19 ;
     RECT  22.66 38.1 23.06 38.19 ;
     RECT  25.39 38.1 25.7 38.19 ;
     RECT  25.76 38.1 58.42 38.19 ;
     RECT  58.55 38.155 58.8 38.19 ;
     RECT  59.93 37.98 60.25 38.19 ;
     RECT  62.1 38.06 63.94 38.19 ;
     RECT  64.95 37.96 65.26 38.19 ;
     RECT  65.32 38.18 70.38 38.19 ;
     RECT  71.77 37.98 72.11 38.19 ;
     RECT  73.61 37.98 73.95 38.19 ;
     RECT  74.12 37.97 74.43 38.19 ;
     RECT  10.69 38.19 11.13 38.23 ;
     RECT  71.67 38.19 72.11 38.23 ;
     RECT  73.51 38.19 73.95 38.23 ;
     RECT  10.69 38.23 11.03 38.29 ;
     RECT  71.77 38.23 72.11 38.29 ;
     RECT  73.61 38.23 73.95 38.29 ;
     RECT  5.52 38.19 5.98 39.1 ;
     RECT  6.9 38.18 10.58 39.1 ;
     RECT  10.61 38.29 12.39 39.1 ;
     RECT  12.42 38.19 13.8 39.1 ;
     RECT  17.48 38.19 21.16 39.1 ;
     RECT  25.3 38.19 63.94 39.1 ;
     RECT  64.86 38.19 70.38 39.1 ;
     RECT  70.41 38.29 72.19 39.1 ;
     RECT  72.25 38.29 74.03 39.1 ;
     RECT  74.06 38.19 74.52 39.1 ;
     RECT  68.57 42.5 70.35 43.31 ;
     RECT  70.41 42.5 72.19 43.31 ;
     RECT  72.25 42.5 74.03 43.31 ;
     RECT  68.65 43.31 68.99 43.37 ;
     RECT  71.77 43.31 72.11 43.37 ;
     RECT  73.61 43.31 73.95 43.37 ;
     RECT  5.52 42.5 5.98 43.41 ;
     RECT  6.9 42.5 39.56 43.41 ;
     RECT  43.24 42.5 45.54 43.41 ;
     RECT  51.98 42.5 54.28 43.41 ;
     RECT  58.88 42.5 68.54 43.41 ;
     RECT  68.65 43.37 69.09 43.41 ;
     RECT  71.67 43.37 72.11 43.41 ;
     RECT  73.51 43.37 73.95 43.41 ;
     RECT  74.06 42.5 74.52 43.41 ;
     RECT  6.9 43.41 10.58 43.42 ;
     RECT  11.96 43.41 15.64 43.42 ;
     RECT  71.77 43.41 72.11 43.42 ;
     RECT  11.61 43.41 11.86 43.445 ;
     RECT  13.01 43.42 13.21 43.445 ;
     RECT  40.59 43.41 40.84 43.445 ;
     RECT  47.51 43.42 47.71 43.445 ;
     RECT  55.33 43.42 55.53 43.445 ;
     RECT  11.61 43.445 11.88 43.5 ;
     RECT  12.09 43.42 12.41 43.5 ;
     RECT  17.02 43.41 18.86 43.5 ;
     RECT  18.99 43.41 19.24 43.5 ;
     RECT  24.84 43.41 39.56 43.5 ;
     RECT  40.59 43.445 40.86 43.5 ;
     RECT  55.79 43.42 56.11 43.5 ;
     RECT  61.18 43.41 68.54 43.5 ;
     RECT  68.65 43.41 68.99 43.5 ;
     RECT  17.02 43.5 19.32 43.54 ;
     RECT  24.84 43.5 41.86 43.54 ;
     RECT  43.24 43.41 45.08 43.54 ;
     RECT  49.22 42.5 51.06 43.54 ;
     RECT  61.18 43.5 69.92 43.54 ;
     RECT  7.9 43.42 8.27 43.595 ;
     RECT  10.71 43.41 10.96 43.595 ;
     RECT  14.39 43.42 14.64 43.595 ;
     RECT  15.77 43.41 16.02 43.595 ;
     RECT  10.13 43.42 10.45 43.62 ;
     RECT  10.71 43.595 10.91 43.62 ;
     RECT  14.39 43.595 14.59 43.62 ;
     RECT  15.77 43.595 15.97 43.62 ;
     RECT  17.15 43.54 17.47 43.62 ;
     RECT  20.37 43.41 20.69 43.62 ;
     RECT  22.67 43.41 22.99 43.62 ;
     RECT  43.37 43.54 43.69 43.62 ;
     RECT  49.35 43.54 49.67 43.62 ;
     RECT  59.01 43.41 59.33 43.62 ;
     RECT  71.77 43.42 72.21 43.62 ;
     RECT  73.61 43.41 73.95 43.62 ;
     RECT  5.61 43.41 5.92 43.63 ;
     RECT  6.09 43.42 6.43 43.63 ;
     RECT  7.93 43.595 8.27 43.63 ;
     RECT  9.77 43.42 10.11 43.63 ;
     RECT  11.5 43.5 12.88 43.63 ;
     RECT  13.01 43.445 13.26 43.63 ;
     RECT  17.94 43.54 19.32 43.63 ;
     RECT  19.45 43.42 19.77 43.63 ;
     RECT  24.96 43.54 25.36 43.63 ;
     RECT  25.39 43.54 25.7 43.63 ;
     RECT  25.76 43.54 41.86 43.63 ;
     RECT  41.99 43.42 42.31 43.63 ;
     RECT  45.17 43.41 45.48 43.63 ;
     RECT  46.93 43.42 47.25 43.63 ;
     RECT  47.51 43.445 47.76 43.63 ;
     RECT  48.89 43.42 49.21 43.63 ;
     RECT  53.83 43.41 54.15 43.63 ;
     RECT  55.28 43.445 55.53 43.63 ;
     RECT  55.66 43.5 57.5 43.63 ;
     RECT  59.81 43.42 60.15 43.63 ;
     RECT  61.3 43.54 61.7 43.63 ;
     RECT  64.95 43.54 65.26 43.63 ;
     RECT  67.17 43.54 67.49 43.63 ;
     RECT  67.62 43.54 69.92 43.63 ;
     RECT  70.03 43.42 70.37 43.63 ;
     RECT  71.87 43.62 72.21 43.63 ;
     RECT  74.12 43.41 74.43 43.63 ;
     RECT  6.09 43.63 6.53 43.67 ;
     RECT  7.93 43.63 8.37 43.67 ;
     RECT  9.77 43.63 10.21 43.67 ;
     RECT  59.71 43.63 60.15 43.67 ;
     RECT  70.03 43.63 70.47 43.67 ;
     RECT  71.87 43.63 72.31 43.67 ;
     RECT  6.09 43.67 6.43 43.73 ;
     RECT  7.93 43.67 8.27 43.73 ;
     RECT  9.77 43.67 10.11 43.73 ;
     RECT  59.81 43.67 60.15 43.73 ;
     RECT  70.03 43.67 70.37 43.73 ;
     RECT  71.87 43.67 72.21 43.73 ;
     RECT  5.52 43.63 5.98 44.54 ;
     RECT  6.01 43.73 7.79 44.54 ;
     RECT  7.85 43.73 9.63 44.54 ;
     RECT  9.69 43.73 11.47 44.54 ;
     RECT  11.5 43.63 14.26 44.54 ;
     RECT  17.94 43.63 21.62 44.54 ;
     RECT  25.3 43.63 44.16 44.54 ;
     RECT  45.08 43.63 51.06 44.54 ;
     RECT  51.98 43.63 57.5 44.54 ;
     RECT  58.45 43.73 60.23 44.54 ;
     RECT  64.86 43.63 69.92 44.54 ;
     RECT  69.95 43.73 71.73 44.54 ;
     RECT  71.79 43.73 73.57 44.54 ;
     RECT  74.06 43.63 74.52 44.54 ;
     RECT  6.01 47.94 7.79 48.75 ;
     RECT  7.85 47.94 9.63 48.75 ;
     RECT  9.69 47.94 11.47 48.75 ;
     RECT  60.29 47.94 62.07 48.75 ;
     RECT  62.13 47.94 63.91 48.75 ;
     RECT  63.97 47.94 65.75 48.75 ;
     RECT  70.41 47.94 72.19 48.75 ;
     RECT  72.25 47.94 74.03 48.75 ;
     RECT  6.09 48.75 6.43 48.81 ;
     RECT  7.93 48.75 8.27 48.81 ;
     RECT  9.77 48.75 10.11 48.81 ;
     RECT  60.37 48.75 60.71 48.81 ;
     RECT  62.21 48.75 62.55 48.81 ;
     RECT  64.05 48.75 64.39 48.81 ;
     RECT  71.77 48.75 72.11 48.81 ;
     RECT  73.61 48.75 73.95 48.81 ;
     RECT  5.52 47.94 5.98 48.85 ;
     RECT  6.09 48.81 6.53 48.85 ;
     RECT  7.93 48.81 8.37 48.85 ;
     RECT  9.77 48.81 10.21 48.85 ;
     RECT  11.96 47.94 32.2 48.85 ;
     RECT  35.88 47.94 60.26 48.85 ;
     RECT  60.37 48.81 60.81 48.85 ;
     RECT  62.21 48.81 62.65 48.85 ;
     RECT  64.05 48.81 64.49 48.85 ;
     RECT  71.67 48.81 72.11 48.85 ;
     RECT  73.51 48.81 73.95 48.85 ;
     RECT  74.06 47.94 74.52 48.85 ;
     RECT  11.96 48.85 18.86 48.86 ;
     RECT  18.99 48.85 19.24 48.86 ;
     RECT  9.33 48.86 9.53 48.885 ;
     RECT  10.71 48.86 10.91 48.885 ;
     RECT  52.57 48.86 52.77 48.885 ;
     RECT  67.27 48.85 67.52 48.885 ;
     RECT  69.59 48.86 69.79 48.885 ;
     RECT  24.84 48.85 32.2 48.94 ;
     RECT  33.24 48.85 33.64 48.94 ;
     RECT  35.88 48.85 37.72 48.94 ;
     RECT  37.85 48.85 38.17 48.94 ;
     RECT  40.15 48.85 40.4 48.94 ;
     RECT  40.6 48.85 41 48.94 ;
     RECT  41.53 48.85 41.85 48.94 ;
     RECT  43.7 48.85 45.08 48.94 ;
     RECT  45.17 48.85 45.48 48.94 ;
     RECT  45.54 48.85 48.76 48.94 ;
     RECT  63.15 48.86 63.47 48.94 ;
     RECT  64.05 48.85 64.39 48.94 ;
     RECT  65.45 48.86 65.77 48.94 ;
     RECT  67.27 48.885 67.54 48.94 ;
     RECT  24.84 48.94 48.76 48.98 ;
     RECT  53.36 48.85 56.58 48.98 ;
     RECT  58.88 48.85 60.26 48.98 ;
     RECT  14.39 48.86 14.64 49.035 ;
     RECT  58.5 48.85 58.75 49.035 ;
     RECT  58.96 48.98 59.26 49.035 ;
     RECT  6.09 48.85 6.43 49.06 ;
     RECT  7.03 48.86 7.35 49.06 ;
     RECT  7.93 48.85 8.27 49.06 ;
     RECT  9.33 48.885 9.58 49.06 ;
     RECT  9.77 48.85 10.11 49.06 ;
     RECT  12.09 48.86 12.41 49.06 ;
     RECT  14.39 49.035 14.59 49.06 ;
     RECT  20.37 48.85 20.69 49.06 ;
     RECT  22.67 48.85 22.99 49.06 ;
     RECT  48.89 48.85 49.21 49.06 ;
     RECT  52.91 48.85 53.23 49.06 ;
     RECT  53.49 48.98 53.81 49.06 ;
     RECT  58.55 49.035 58.75 49.06 ;
     RECT  60.37 48.85 60.71 49.06 ;
     RECT  62.21 48.85 62.55 49.06 ;
     RECT  65.32 48.94 68.54 49.06 ;
     RECT  69.54 48.885 69.79 49.06 ;
     RECT  71.77 48.85 72.11 49.06 ;
     RECT  73.61 48.85 73.95 49.06 ;
     RECT  5.61 48.85 5.92 49.07 ;
     RECT  6.9 49.06 10.58 49.07 ;
     RECT  10.71 48.885 10.96 49.07 ;
     RECT  15.64 48.86 18.86 49.07 ;
     RECT  18.99 48.86 19.31 49.07 ;
     RECT  24.96 48.98 25.36 49.07 ;
     RECT  25.39 48.98 25.7 49.07 ;
     RECT  25.76 48.98 47.84 49.07 ;
     RECT  52.57 48.885 52.82 49.07 ;
     RECT  54.74 48.98 56.12 49.07 ;
     RECT  58.96 49.035 59.24 49.07 ;
     RECT  63.02 48.94 64.86 49.07 ;
     RECT  64.95 48.84 65.26 49.07 ;
     RECT  65.32 49.06 72.22 49.07 ;
     RECT  72.33 48.86 72.67 49.07 ;
     RECT  74.12 48.85 74.43 49.07 ;
     RECT  56.57 49.07 56.72 49.08 ;
     RECT  57.02 49.07 59.34 49.08 ;
     RECT  52.44 49.07 56.12 49.09 ;
     RECT  57.04 49.08 59.34 49.09 ;
     RECT  72.33 49.07 72.77 49.11 ;
     RECT  72.33 49.11 72.67 49.17 ;
     RECT  5.52 49.07 5.98 49.98 ;
     RECT  6.9 49.07 11.96 49.98 ;
     RECT  15.64 49.07 21.16 49.98 ;
     RECT  25.3 49.07 47.84 49.98 ;
     RECT  52.44 49.09 59.34 49.98 ;
     RECT  63.02 49.07 72.22 49.98 ;
     RECT  72.25 49.17 74.03 49.98 ;
     RECT  74.06 49.07 74.52 49.98 ;
     RECT  10.61 53.38 12.39 54.19 ;
     RECT  72.25 53.38 74.03 54.19 ;
     RECT  10.69 54.19 11.03 54.25 ;
     RECT  73.61 54.19 73.95 54.25 ;
     RECT  5.52 53.38 5.98 54.29 ;
     RECT  10.69 54.25 11.13 54.29 ;
     RECT  13.34 53.38 17.48 54.29 ;
     RECT  18.4 53.38 44.16 54.29 ;
     RECT  45.08 53.38 66.7 54.29 ;
     RECT  67.16 53.38 72.22 54.29 ;
     RECT  73.51 54.25 73.95 54.29 ;
     RECT  74.06 53.38 74.52 54.29 ;
     RECT  6.9 53.38 10.58 54.3 ;
     RECT  45.54 54.29 65.32 54.3 ;
     RECT  68.54 54.29 72.22 54.3 ;
     RECT  9.79 54.3 9.99 54.325 ;
     RECT  13.01 54.3 13.21 54.325 ;
     RECT  61.77 54.3 61.97 54.325 ;
     RECT  70.05 54.3 70.25 54.325 ;
     RECT  11.17 54.3 11.49 54.38 ;
     RECT  22.08 54.29 44.16 54.38 ;
     RECT  45.17 54.29 45.48 54.38 ;
     RECT  45.54 54.3 61.64 54.38 ;
     RECT  15.64 54.29 17.48 54.42 ;
     RECT  22.08 54.38 61.64 54.42 ;
     RECT  7.9 54.3 8.27 54.475 ;
     RECT  18.53 54.29 18.78 54.475 ;
     RECT  62.64 54.3 62.89 54.475 ;
     RECT  65.45 54.29 65.7 54.475 ;
     RECT  68.16 54.29 68.41 54.475 ;
     RECT  69.54 54.3 69.79 54.475 ;
     RECT  10.13 54.3 10.45 54.5 ;
     RECT  10.69 54.29 11.03 54.5 ;
     RECT  13.47 54.29 13.79 54.5 ;
     RECT  15.77 54.42 16.09 54.5 ;
     RECT  18.53 54.475 18.73 54.5 ;
     RECT  19.91 54.29 20.23 54.5 ;
     RECT  58.88 54.42 60.72 54.5 ;
     RECT  61.72 54.325 61.97 54.5 ;
     RECT  62.69 54.475 62.89 54.5 ;
     RECT  63.95 54.3 64.27 54.5 ;
     RECT  64.87 54.3 65.26 54.5 ;
     RECT  65.45 54.475 65.65 54.5 ;
     RECT  68.21 54.475 68.41 54.5 ;
     RECT  69.59 54.475 69.79 54.5 ;
     RECT  5.61 54.29 5.92 54.51 ;
     RECT  6.09 54.3 6.43 54.51 ;
     RECT  7.93 54.475 8.27 54.51 ;
     RECT  9.79 54.325 10.04 54.51 ;
     RECT  11.04 54.38 12.88 54.51 ;
     RECT  13.01 54.325 13.26 54.51 ;
     RECT  14.39 54.3 14.71 54.51 ;
     RECT  20.37 54.3 20.69 54.51 ;
     RECT  22.2 54.42 24.38 54.51 ;
     RECT  25.39 54.42 25.7 54.51 ;
     RECT  25.76 54.42 55.2 54.51 ;
     RECT  64.95 54.5 65.26 54.51 ;
     RECT  70 54.325 70.25 54.51 ;
     RECT  71.77 54.3 72.11 54.51 ;
     RECT  73.61 54.29 73.95 54.51 ;
     RECT  74.12 54.29 74.43 54.51 ;
     RECT  6.09 54.51 6.53 54.55 ;
     RECT  7.93 54.51 8.37 54.55 ;
     RECT  71.67 54.51 72.11 54.55 ;
     RECT  73.51 54.51 73.95 54.55 ;
     RECT  6.09 54.55 6.43 54.61 ;
     RECT  7.93 54.55 8.27 54.61 ;
     RECT  71.77 54.55 72.11 54.61 ;
     RECT  73.61 54.55 73.95 54.61 ;
     RECT  5.52 54.51 5.98 55.42 ;
     RECT  6.01 54.61 7.79 55.42 ;
     RECT  7.85 54.61 9.63 55.42 ;
     RECT  9.66 54.51 16.56 55.42 ;
     RECT  20.24 54.51 24.38 55.42 ;
     RECT  25.3 54.51 55.2 55.42 ;
     RECT  58.88 54.5 64.4 55.42 ;
     RECT  64.86 54.51 65.32 55.42 ;
     RECT  69 54.51 70.38 55.42 ;
     RECT  70.41 54.61 72.19 55.42 ;
     RECT  72.25 54.61 74.03 55.42 ;
     RECT  74.06 54.51 74.52 55.42 ;
     RECT  6.01 58.82 7.79 59.63 ;
     RECT  72.25 58.82 74.03 59.63 ;
     RECT  6.09 59.63 6.43 59.69 ;
     RECT  73.61 59.63 73.95 59.69 ;
     RECT  5.52 58.82 5.98 59.73 ;
     RECT  6.09 59.69 6.53 59.73 ;
     RECT  8.74 58.82 11.04 59.73 ;
     RECT  17.02 58.82 41.4 59.73 ;
     RECT  45.08 58.82 63.48 59.73 ;
     RECT  67.16 58.82 72.22 59.73 ;
     RECT  73.51 59.69 73.95 59.73 ;
     RECT  74.06 58.82 74.52 59.73 ;
     RECT  68.54 59.73 72.22 59.74 ;
     RECT  7.95 59.74 8.15 59.765 ;
     RECT  18.06 59.73 18.46 59.82 ;
     RECT  19.32 59.73 41.4 59.82 ;
     RECT  45.17 59.73 45.48 59.82 ;
     RECT  45.54 59.73 62.1 59.82 ;
     RECT  62.69 59.74 63.01 59.82 ;
     RECT  63.1 59.73 63.35 59.82 ;
     RECT  65.45 59.74 65.77 59.82 ;
     RECT  14.72 58.82 16.56 59.86 ;
     RECT  17.94 59.82 64.4 59.86 ;
     RECT  8.87 59.73 9.19 59.94 ;
     RECT  14.85 59.86 15.17 59.94 ;
     RECT  17.15 59.73 17.47 59.94 ;
     RECT  69.54 59.74 69.79 59.94 ;
     RECT  71.77 59.74 72.09 59.94 ;
     RECT  5.61 59.73 5.92 59.95 ;
     RECT  6.09 59.73 6.43 59.95 ;
     RECT  7.95 59.765 8.2 59.95 ;
     RECT  9.33 59.74 9.65 59.95 ;
     RECT  15.77 59.86 16.09 59.95 ;
     RECT  17.94 59.86 25.3 59.95 ;
     RECT  25.39 59.86 25.7 59.95 ;
     RECT  25.76 59.86 64.4 59.95 ;
     RECT  64.95 59.72 65.26 59.95 ;
     RECT  65.32 59.82 67.16 59.95 ;
     RECT  68.16 59.73 68.41 59.95 ;
     RECT  68.54 59.94 72.22 59.95 ;
     RECT  73.61 59.73 73.95 59.95 ;
     RECT  74.12 59.73 74.43 59.95 ;
     RECT  6.09 59.95 6.53 59.99 ;
     RECT  73.51 59.95 73.95 59.99 ;
     RECT  6.09 59.99 6.43 60.05 ;
     RECT  73.61 59.99 73.95 60.05 ;
     RECT  5.52 59.95 5.98 60.86 ;
     RECT  6.01 60.05 7.79 60.86 ;
     RECT  7.82 59.95 11.5 60.86 ;
     RECT  15.64 59.95 64.4 60.86 ;
     RECT  64.86 59.95 72.22 60.86 ;
     RECT  72.25 60.05 74.03 60.86 ;
     RECT  74.06 59.95 74.52 60.86 ;
     RECT  6.01 64.26 7.79 65.07 ;
     RECT  70.41 64.26 72.19 65.07 ;
     RECT  72.25 64.26 74.03 65.07 ;
     RECT  6.09 65.07 6.43 65.13 ;
     RECT  71.77 65.07 72.11 65.13 ;
     RECT  73.61 65.07 73.95 65.13 ;
     RECT  5.52 64.26 5.98 65.17 ;
     RECT  6.09 65.13 6.53 65.17 ;
     RECT  7.82 64.26 11.5 65.17 ;
     RECT  15.18 64.26 17.48 65.17 ;
     RECT  21.62 64.26 31.28 65.17 ;
     RECT  34.96 64.26 44.16 65.17 ;
     RECT  45.08 64.26 62.1 65.17 ;
     RECT  63.02 64.26 69.92 65.17 ;
     RECT  71.67 65.13 72.11 65.17 ;
     RECT  73.51 65.13 73.95 65.17 ;
     RECT  74.06 64.26 74.52 65.17 ;
     RECT  63.02 65.17 66.7 65.18 ;
     RECT  10.69 65.17 10.94 65.205 ;
     RECT  12.09 65.18 12.29 65.205 ;
     RECT  19.91 65.18 20.11 65.205 ;
     RECT  10.69 65.205 10.96 65.26 ;
     RECT  15.77 65.18 16.09 65.26 ;
     RECT  23.59 65.18 23.91 65.26 ;
     RECT  23.92 65.17 31.28 65.26 ;
     RECT  34.96 65.17 38.18 65.26 ;
     RECT  38.31 65.17 38.56 65.26 ;
     RECT  41.06 65.17 41.46 65.26 ;
     RECT  41.99 65.17 42.31 65.26 ;
     RECT  45.17 65.17 45.48 65.26 ;
     RECT  45.54 65.17 62.1 65.26 ;
     RECT  63.15 65.18 63.47 65.26 ;
     RECT  64.02 65.18 64.27 65.26 ;
     RECT  65.45 65.18 65.77 65.26 ;
     RECT  66.25 65.18 66.57 65.26 ;
     RECT  66.83 65.17 67.08 65.26 ;
     RECT  23.46 65.26 31.28 65.3 ;
     RECT  34.96 65.26 38.64 65.3 ;
     RECT  68.08 65.17 69.92 65.3 ;
     RECT  7.95 65.17 8.2 65.355 ;
     RECT  36.91 65.3 37.18 65.355 ;
     RECT  7.95 65.355 8.15 65.38 ;
     RECT  9.33 65.17 9.65 65.38 ;
     RECT  15.31 65.17 15.63 65.38 ;
     RECT  21.75 65.17 22.07 65.38 ;
     RECT  35.09 65.3 35.41 65.38 ;
     RECT  39.69 65.17 40.01 65.38 ;
     RECT  68.16 65.3 68.53 65.38 ;
     RECT  69.54 65.3 69.79 65.38 ;
     RECT  71.77 65.17 72.11 65.38 ;
     RECT  5.61 65.17 5.92 65.39 ;
     RECT  6.09 65.17 6.43 65.39 ;
     RECT  8.41 65.18 8.73 65.39 ;
     RECT  10.58 65.26 11.96 65.39 ;
     RECT  12.09 65.205 12.34 65.39 ;
     RECT  13.47 65.18 13.79 65.39 ;
     RECT  15.64 65.26 17.48 65.39 ;
     RECT  19.33 65.18 19.65 65.39 ;
     RECT  19.91 65.205 20.16 65.39 ;
     RECT  21.29 65.18 21.61 65.39 ;
     RECT  23.46 65.3 25.3 65.39 ;
     RECT  25.39 65.3 25.7 65.39 ;
     RECT  29.44 65.3 31.28 65.39 ;
     RECT  31.41 65.18 31.73 65.39 ;
     RECT  36.91 65.355 37.16 65.39 ;
     RECT  37.26 65.3 38.64 65.39 ;
     RECT  38.77 65.18 39.09 65.39 ;
     RECT  40.94 65.26 64.86 65.39 ;
     RECT  64.95 65.18 65.26 65.39 ;
     RECT  65.32 65.26 67.16 65.39 ;
     RECT  68.16 65.38 68.41 65.39 ;
     RECT  68.54 65.38 72.22 65.39 ;
     RECT  73.61 65.17 73.95 65.39 ;
     RECT  74.12 65.17 74.43 65.39 ;
     RECT  6.09 65.39 6.53 65.43 ;
     RECT  73.51 65.39 73.95 65.43 ;
     RECT  6.09 65.43 6.43 65.49 ;
     RECT  73.61 65.43 73.95 65.49 ;
     RECT  5.52 65.39 5.98 66.3 ;
     RECT  6.01 65.49 7.79 66.3 ;
     RECT  8.28 65.39 25.76 66.3 ;
     RECT  29.44 65.39 33.58 66.3 ;
     RECT  37.26 65.39 72.22 66.3 ;
     RECT  72.25 65.49 74.03 66.3 ;
     RECT  74.06 65.39 74.52 66.3 ;
     RECT  5.52 69.7 5.98 70.61 ;
     RECT  10.12 69.7 27.14 70.61 ;
     RECT  28.06 69.7 34.04 70.61 ;
     RECT  34.96 69.7 68.54 70.61 ;
     RECT  69 69.7 74.52 70.61 ;
     RECT  45.54 70.61 50.6 70.62 ;
     RECT  69 70.61 72.68 70.62 ;
     RECT  51.65 70.62 51.85 70.645 ;
     RECT  70.95 70.62 71.2 70.645 ;
     RECT  6.1 70.61 6.5 70.7 ;
     RECT  10.25 70.61 10.57 70.7 ;
     RECT  12.42 70.61 15.64 70.7 ;
     RECT  15.77 70.61 16.09 70.7 ;
     RECT  17.94 70.61 27.14 70.7 ;
     RECT  29.91 70.61 30.23 70.7 ;
     RECT  32.21 70.61 32.53 70.7 ;
     RECT  33.24 70.61 33.64 70.7 ;
     RECT  33.66 70.61 33.91 70.7 ;
     RECT  36.81 70.61 37.13 70.7 ;
     RECT  37.39 70.61 37.64 70.7 ;
     RECT  38.77 70.61 39.09 70.7 ;
     RECT  69.13 70.62 69.45 70.7 ;
     RECT  70 70.62 70.25 70.7 ;
     RECT  70.95 70.645 71.22 70.7 ;
     RECT  5.98 70.7 40.48 70.74 ;
     RECT  43.24 70.61 45.08 70.74 ;
     RECT  45.54 70.62 46.92 70.74 ;
     RECT  51.98 70.61 68.54 70.74 ;
     RECT  45.65 70.74 45.92 70.795 ;
     RECT  47.92 70.62 48.17 70.795 ;
     RECT  50.73 70.61 50.98 70.795 ;
     RECT  72.81 70.61 73.06 70.795 ;
     RECT  25.39 70.74 25.75 70.82 ;
     RECT  41.07 70.61 41.39 70.82 ;
     RECT  43.37 70.74 43.69 70.82 ;
     RECT  47.97 70.795 48.17 70.82 ;
     RECT  50.15 70.62 50.47 70.82 ;
     RECT  50.73 70.795 50.93 70.82 ;
     RECT  66.83 70.74 67.15 70.82 ;
     RECT  72.23 70.62 72.55 70.82 ;
     RECT  72.81 70.795 73.01 70.82 ;
     RECT  5.61 70.61 5.92 70.83 ;
     RECT  5.98 70.74 20.7 70.83 ;
     RECT  25.39 70.82 25.7 70.83 ;
     RECT  25.76 70.74 40.48 70.83 ;
     RECT  44.29 70.74 44.54 70.83 ;
     RECT  45.17 70.61 45.48 70.83 ;
     RECT  45.65 70.795 45.9 70.83 ;
     RECT  46.54 70.74 46.79 70.83 ;
     RECT  51.6 70.645 51.85 70.83 ;
     RECT  51.98 70.74 53.82 70.83 ;
     RECT  54.82 70.74 55.07 70.83 ;
     RECT  55.2 70.74 57.04 70.83 ;
     RECT  57.63 70.74 57.88 70.83 ;
     RECT  59.46 70.74 59.86 70.83 ;
     RECT  64.95 70.74 65.26 70.83 ;
     RECT  73.61 70.62 73.95 70.83 ;
     RECT  74.12 70.61 74.43 70.83 ;
     RECT  73.51 70.83 73.95 70.87 ;
     RECT  73.61 70.87 73.95 70.93 ;
     RECT  5.52 70.83 20.7 71.74 ;
     RECT  25.3 70.83 40.48 71.74 ;
     RECT  44.16 70.83 46.92 71.74 ;
     RECT  50.6 70.83 57.04 71.74 ;
     RECT  57.5 70.83 58.88 71.74 ;
     RECT  62.56 70.74 64.4 71.74 ;
     RECT  64.86 70.83 65.32 71.74 ;
     RECT  69 70.7 72.22 71.74 ;
     RECT  72.25 70.93 74.03 71.74 ;
     RECT  74.06 70.83 74.52 71.74 ;
     RECT  5.52 75.14 35.42 76.05 ;
     RECT  41.4 75.14 49.22 76.05 ;
     RECT  74.06 75.14 74.52 76.05 ;
     RECT  41.4 76.05 45.08 76.06 ;
     RECT  45.54 76.05 49.22 76.06 ;
     RECT  49.68 75.14 68.08 76.06 ;
     RECT  5.98 76.05 35.42 76.14 ;
     RECT  57.62 76.06 58.02 76.14 ;
     RECT  59.47 76.06 59.72 76.14 ;
     RECT  60.72 76.06 68.08 76.14 ;
     RECT  71.76 75.14 73.6 76.14 ;
     RECT  5.98 76.14 36.34 76.18 ;
     RECT  39.1 75.14 40.94 76.18 ;
     RECT  57.5 76.14 74.06 76.18 ;
     RECT  42.4 76.06 42.65 76.235 ;
     RECT  46.54 76.06 46.91 76.235 ;
     RECT  50.68 76.06 50.93 76.235 ;
     RECT  42.45 76.235 42.65 76.26 ;
     RECT  44.63 76.06 44.95 76.26 ;
     RECT  48.77 76.06 49.09 76.26 ;
     RECT  50.73 76.235 50.93 76.26 ;
     RECT  52.91 76.06 53.23 76.26 ;
     RECT  53.49 76.06 53.81 76.26 ;
     RECT  57.17 76.06 57.49 76.26 ;
     RECT  5.61 76.05 5.92 76.27 ;
     RECT  5.98 76.18 20.7 76.27 ;
     RECT  20.82 76.18 21.22 76.27 ;
     RECT  25.39 76.18 25.7 76.27 ;
     RECT  28.18 76.18 28.58 76.27 ;
     RECT  32.77 76.18 33.11 76.27 ;
     RECT  37.37 76.06 37.71 76.27 ;
     RECT  39.21 76.18 39.55 76.27 ;
     RECT  45.17 76.05 45.48 76.27 ;
     RECT  46.57 76.235 46.91 76.27 ;
     RECT  48.41 76.06 48.75 76.27 ;
     RECT  50.25 76.06 50.59 76.27 ;
     RECT  52.09 76.06 52.43 76.27 ;
     RECT  53.93 76.06 54.27 76.27 ;
     RECT  55.77 76.06 56.11 76.27 ;
     RECT  57.5 76.18 64.86 76.27 ;
     RECT  64.95 76.18 65.26 76.27 ;
     RECT  65.32 76.18 74.06 76.27 ;
     RECT  74.12 76.05 74.43 76.27 ;
     RECT  32.77 76.27 33.21 76.31 ;
     RECT  37.37 76.27 37.81 76.31 ;
     RECT  39.21 76.27 39.65 76.31 ;
     RECT  46.57 76.27 47.01 76.31 ;
     RECT  48.41 76.27 48.85 76.31 ;
     RECT  50.25 76.27 50.69 76.31 ;
     RECT  52.09 76.27 52.53 76.31 ;
     RECT  53.93 76.27 54.37 76.31 ;
     RECT  55.77 76.27 56.21 76.31 ;
     RECT  32.77 76.31 33.11 76.37 ;
     RECT  37.37 76.31 37.71 76.37 ;
     RECT  39.21 76.31 39.55 76.37 ;
     RECT  46.57 76.31 46.91 76.37 ;
     RECT  48.41 76.31 48.75 76.37 ;
     RECT  50.25 76.31 50.59 76.37 ;
     RECT  52.09 76.31 52.43 76.37 ;
     RECT  53.93 76.31 54.27 76.37 ;
     RECT  55.77 76.31 56.11 76.37 ;
     RECT  5.52 76.27 20.7 77.18 ;
     RECT  25.3 76.27 25.76 77.18 ;
     RECT  29.44 76.18 32.66 77.18 ;
     RECT  32.69 76.37 34.47 77.18 ;
     RECT  34.5 76.18 36.34 77.18 ;
     RECT  37.29 76.37 39.07 77.18 ;
     RECT  39.13 76.37 40.91 77.18 ;
     RECT  45.08 76.27 45.54 77.18 ;
     RECT  46.49 76.37 48.27 77.18 ;
     RECT  48.33 76.37 50.11 77.18 ;
     RECT  50.17 76.37 51.95 77.18 ;
     RECT  52.01 76.37 53.79 77.18 ;
     RECT  53.85 76.37 55.63 77.18 ;
     RECT  55.69 76.37 57.47 77.18 ;
     RECT  57.5 76.27 74.52 77.18 ;
    LAYER li1 ;
     RECT  5.52 10.795 74.52 78.97 ;
    LAYER met1 ;
     RECT  1.08 47.36 2.92 47.5 ;
     RECT  2 64.02 3.38 64.16 ;
     RECT  2.92 44.3 5.52 47.5 ;
     RECT  3.38 60.96 5.52 64.16 ;
     RECT  48 90.2 49.52 90.34 ;
     RECT  5.52 10.64 74.52 79.12 ;
     RECT  74.52 33.42 74.82 43.08 ;
     RECT  74.52 58.92 74.82 71.3 ;
     RECT  74.82 39.2 77.12 39.34 ;
     RECT  74.82 60.96 77.12 64.16 ;
     RECT  77.12 64.02 78.04 64.16 ;
    LAYER met2 ;
     RECT  30.52 0.07 31.12 0.14 ;
     RECT  24.08 0.14 49.98 10.695 ;
     RECT  11.51 10.695 12.41 12 ;
     RECT  24.08 10.695 52.41 12 ;
     RECT  11.51 12 55.96 13.02 ;
     RECT  11.51 13.02 57.8 13.415 ;
     RECT  71.51 10.695 72.41 13.415 ;
     RECT  10.07 13.415 57.8 15.2 ;
     RECT  10.07 15.2 54.12 17.24 ;
     RECT  10.07 17.24 53.66 26.08 ;
     RECT  10.07 26.08 40.32 26.28 ;
     RECT  7.98 26.28 40.32 26.42 ;
     RECT  50.07 26.08 53.66 28.32 ;
     RECT  70.07 13.415 72.41 28.32 ;
     RECT  7.98 26.42 39.4 31.38 ;
     RECT  6.14 31.38 39.4 31.52 ;
     RECT  50.07 28.32 72.41 32.06 ;
     RECT  6.14 31.52 32.41 32.91 ;
     RECT  50.07 32.06 73.44 32.91 ;
     RECT  50.07 32.91 74.82 39.2 ;
     RECT  50.07 39.2 77.12 39.88 ;
     RECT  5.68 32.91 32.41 42.43 ;
     RECT  46.62 39.88 77.12 42.57 ;
     RECT  46.62 42.57 74.82 43.08 ;
     RECT  46.62 43.08 73.9 44.64 ;
     RECT  2.92 42.43 32.41 45.15 ;
     RECT  1.08 45.15 32.41 47.5 ;
     RECT  5.68 47.5 32.41 48.04 ;
     RECT  42.48 44.64 73.9 48.04 ;
     RECT  5.68 48.04 73.9 51.24 ;
     RECT  5.68 51.24 52.41 57.39 ;
     RECT  61.8 51.24 73.9 57.7 ;
     RECT  63.64 57.7 73.9 58.72 ;
     RECT  3.38 57.39 52.41 58.75 ;
     RECT  65.02 58.72 73.9 58.75 ;
     RECT  65.02 58.75 77.12 60.11 ;
     RECT  2 58.75 52.41 64.16 ;
     RECT  65.02 60.11 78.04 64.16 ;
     RECT  6.14 64.16 52.41 66.54 ;
     RECT  9.36 66.54 52.41 68.58 ;
     RECT  65.02 64.16 73.9 68.92 ;
     RECT  10.07 68.58 52.41 69.26 ;
     RECT  30.07 69.26 52.41 69.46 ;
     RECT  10.07 69.26 17.32 69.6 ;
     RECT  30.07 69.46 52.74 71.84 ;
     RECT  70.07 68.92 73.9 71.98 ;
     RECT  30.07 71.84 59.64 75.04 ;
     RECT  10.07 69.6 12.41 76.345 ;
     RECT  70.07 71.98 72.41 76.345 ;
     RECT  30.07 75.04 56.88 76.74 ;
     RECT  10.07 76.345 10.97 79.065 ;
     RECT  30.07 76.74 55.5 79.065 ;
     RECT  70.07 76.345 70.97 79.065 ;
     RECT  32.36 79.065 55.5 90.78 ;
    LAYER met3 ;
     RECT  0.3 32.83 10.13 60.33 ;
     RECT  10.13 13.435 10.91 79.045 ;
     RECT  10.91 13.435 11.57 76.325 ;
     RECT  11.57 10.715 12.35 76.325 ;
     RECT  30.13 13.435 30.91 79.045 ;
     RECT  30.91 13.435 31.57 76.325 ;
     RECT  31.57 10.715 32.35 76.325 ;
     RECT  50.13 13.435 50.91 79.045 ;
     RECT  50.91 13.435 51.57 76.325 ;
     RECT  51.57 10.715 52.35 76.325 ;
     RECT  70 45.07 70.13 45.37 ;
     RECT  70.13 13.435 70.91 79.045 ;
     RECT  70.91 13.435 71.57 76.325 ;
     RECT  71.57 10.715 72.35 76.325 ;
     RECT  72.35 32.83 79.91 68.49 ;
    LAYER met4 ;
     RECT  10.04 10.64 72.44 79.12 ;
  END
END PLL_ANALOG_MACRO
END LIBRARY
